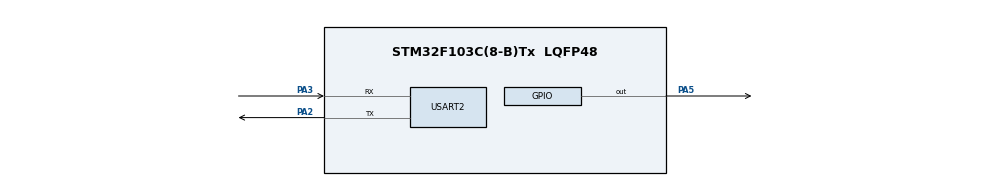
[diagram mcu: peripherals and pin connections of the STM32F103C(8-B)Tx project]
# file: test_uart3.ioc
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Dma.Request0=USART2_RX
Dma.USART2_RX.0.Direction=DMA_PERIPH_TO_MEMORY
Dma.USART2_RX.0.Instance=DMA1_Channel6
Dma.USART2_RX.0.MemDataAlignment=DMA_MDATAALIGN_BYTE
Dma.USART2_RX.0.MemInc=DMA_MINC_ENABLE
Dma.USART2_RX.0.Mode=DMA_NORMAL
Dma.USART2_RX.0.PeriphDataAlignment=DMA_PDATAALIGN_BYTE
Dma.USART2_RX.0.PeriphInc=DMA_PINC_DISABLE
Dma.USART2_RX.0.Priority=DMA_PRIORITY_LOW
Mcu.Family=STM32F1
Mcu.Name=STM32F103C(8-B)Tx
Mcu.Package=LQFP48
NVIC.DMA1_Channel6_IRQn=true\:0\:0\:false\:false\:true\:false\:true
NVIC.PriorityGroup=NVIC_PRIORITYGROUP_4
PA13.Mode=Serial_Wire
PA13.Signal=SYS_JTMS-SWDIO
PA14.Mode=Serial_Wire
PA14.Signal=SYS_JTCK-SWCLK
PA2.Mode=Asynchronous
PA2.Signal=USART2_TX
PA3.Mode=Asynchronous
PA3.Signal=USART2_RX
PA5.Signal=GPIO_Output
PD0-OSC_IN.Mode=HSE-External-Oscillator
PD0-OSC_IN.Signal=RCC_OSC_IN
PD1-OSC_OUT.Mode=HSE-External-Oscillator
PD1-OSC_OUT.Signal=RCC_OSC_OUT
ProjectManager.HeapSize=0x200
ProjectManager.StackSize=0x400
ProjectManager.TargetToolchain=MDK-ARM V5.27
RCC.AHBFreq_Value=72000000
RCC.APB1CLKDivider=RCC_HCLK_DIV2
RCC.APB1Freq_Value=36000000
RCC.APB1TimFreq_Value=72000000
RCC.APB2Freq_Value=72000000
RCC.APB2TimFreq_Value=72000000
RCC.HCLKFreq_Value=72000000
RCC.PLLMUL=RCC_PLL_MUL9
RCC.PLLSourceVirtual=RCC_PLLSOURCE_HSE
RCC.SYSCLKFreq_VALUE=72000000
RCC.SYSCLKSource=RCC_SYSCLKSOURCE_PLLCLK
RCC.USBFreq_Value=72000000
USART2.VirtualMode=VM_ASYNC
board=custom

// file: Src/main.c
#include "stm32f1xx_hal.h"
#include <stdio.h>

UART_HandleTypeDef huart2;

int i; //Khai bao bien dem
char buffer[100]; //Khai bao mang buffer 100 phan tu
int len; //Khai bao bien len tuong ung voi chieu dai
char Rx_indx, Rx_data[2], Rx_Buffer[100], Transfer_cplt; //Khai bao cac bien de nhan du lieu
/* USER CODE END PV */

void SystemClock_Config(void);
static void MX_GPIO_Init(void);
static void MX_USART2_UART_Init(void);

/* USER CODE BEGIN PFP */
/* Private function prototypes -----------------------------------------------*/
#ifdef __GNUC__
  /* With GCC/RAISONANCE, small printf (option LD Linker->Libraries->Small printf
     set to 'Yes') calls __io_putchar() */
  #define PUTCHAR_PROTOTYPE int __io_putchar(int ch)
#else
  #define PUTCHAR_PROTOTYPE int fputc(int ch, FILE *f)
  #define GETCHAR_PROTOTYPE int fgetc(FILE *f)
#endif /* __GNUC__ */
	PUTCHAR_PROTOTYPE
{
  /* Place your implementation of fputc here */
  /* e.g. write a character to the USART */
	HAL_UART_Transmit(&huart2, (uint8_t*)&ch,1,100);

  /* Loop until the end of transmission */

  return ch;
}
//Ham ngat uart
void HAL_UART_RxCpltCallback(UART_HandleTypeDef *huart)
{
	uint8_t i;
	if (huart->Instance == USART3)	//UART hien tai la uart3
		{
		if (Rx_indx==0) {for (i=0;i<100;i++) Rx_Buffer[i]=0;}	//xoa Rx_Buffer truoc khi nhan du lieu

		if (Rx_data[0]!=13)	//Neu du lieu nhan duoc khac voi 13 (13 la ma cua phim enter)
			{
			Rx_Buffer[Rx_indx++]=Rx_data[0];	//them du lieu vao Rx_Buffer
			}
		else			//Neu phim enter duoc an
			{
			Rx_indx=0;	//Dua index ve 0
			Transfer_cplt=1;//Qua trinh truyen hoan tat, du lieu da san sang de doc
			}

		HAL_UART_Receive_IT(&huart2, Rx_data, 1);	//Kich hoat UART nhan du lieu ngat moi luc
		}

}
/* USER CODE END PFP */

int main(void)
{

  /* MCU Configuration----------------------------------------------------------*/

  /* Reset of all peripherals, Initializes the Flash interface and the Systick. */
  HAL_Init();

  /* Configure the system clock */
  SystemClock_Config();

  /* Initialize all configured peripherals */
  MX_GPIO_Init();
  MX_USART2_UART_Init();

  /* USER CODE BEGIN 2 */
	HAL_UART_Receive_IT(&huart2, Rx_data, 1); //Kich hoat ngat uart khi nhan duoc 1 byte
  /* USER CODE END 2 */

  /* Infinite loop */
  while (1)
  {

  /* USER CODE BEGIN 3 */
	printf("Hello\r \n");		// In dong chu Hello len tren may tinh
	printf("Gia tri cua i: %d \r\n",i);
		HAL_Delay(500);
		i++;
	// Gio khong su dung printf nua ma thay vao do su dung sprinf
	sprintf(buffer, "Xin chao\r\n");
	len = strlen(buffer);
	HAL_UART_Transmit(&huart2, buffer, len, 1000);	//Truyen du lieu tren uart3, du lieu o day la buffer co chieu dai la len
	HAL_Delay(500);
//	if (Transfer_cplt)
//	{
//		sprintf(buffer, "%s\r\n", Rx_Buffer);	// IN bufer
//		len = strlen(buffer);	//Lay chieu dai cua buffer
//		HAL_UART_Transmit(&huart2, buffer,len, 1000);	//Truyen buffer voi chieu dai qua uart3
//		Transfer_cplt =0; //Reset lai bien tranfer_complete
//		HAL_Delay(500);
//	}
  }
  /* USER CODE END 3 */

}

/** System Clock Configuration
*/
void SystemClock_Config(void)
{

  RCC_OscInitTypeDef RCC_OscInitStruct;
  RCC_ClkInitTypeDef RCC_ClkInitStruct;

  RCC_OscInitStruct.OscillatorType = RCC_OSCILLATORTYPE_HSI;
  RCC_OscInitStruct.HSIState = RCC_HSI_ON;
  RCC_OscInitStruct.HSICalibrationValue = 16;
  RCC_OscInitStruct.PLL.PLLState = RCC_PLL_NONE;
  HAL_RCC_OscConfig(&RCC_OscInitStruct);

  RCC_ClkInitStruct.ClockType = RCC_CLOCKTYPE_HCLK|RCC_CLOCKTYPE_SYSCLK
                              |RCC_CLOCKTYPE_PCLK1|RCC_CLOCKTYPE_PCLK2;
  RCC_ClkInitStruct.SYSCLKSource = RCC_SYSCLKSOURCE_HSI;
  RCC_ClkInitStruct.AHBCLKDivider = RCC_SYSCLK_DIV1;
  RCC_ClkInitStruct.APB1CLKDivider = RCC_HCLK_DIV1;
  RCC_ClkInitStruct.APB2CLKDivider = RCC_HCLK_DIV1;
  HAL_RCC_ClockConfig(&RCC_ClkInitStruct, FLASH_LATENCY_0);

  HAL_SYSTICK_Config(HAL_RCC_GetHCLKFreq()/1000);

  HAL_SYSTICK_CLKSourceConfig(SYSTICK_CLKSOURCE_HCLK);

  /* SysTick_IRQn interrupt configuration */
  HAL_NVIC_SetPriority(SysTick_IRQn, 0, 0);
}

/* USART3 init function */
void MX_USART2_UART_Init(void)
{

  huart2.Instance = USART2;
  huart2.Init.BaudRate = 115200;
  huart2.Init.WordLength = UART_WORDLENGTH_8B;
  huart2.Init.StopBits = UART_STOPBITS_1;
  huart2.Init.Parity = UART_PARITY_NONE;
  huart2.Init.Mode = UART_MODE_TX_RX;
  huart2.Init.HwFlowCtl = UART_HWCONTROL_NONE;
  huart2.Init.OverSampling = UART_OVERSAMPLING_16;
  HAL_UART_Init(&huart2);

}

/** Pinout Configuration
*/
void MX_GPIO_Init(void)
{

  /* GPIO Ports Clock Enable */
  __HAL_RCC_GPIOA_CLK_ENABLE();

}

/************************ (C) COPYRIGHT STMicroelectronics *****END OF FILE****/
